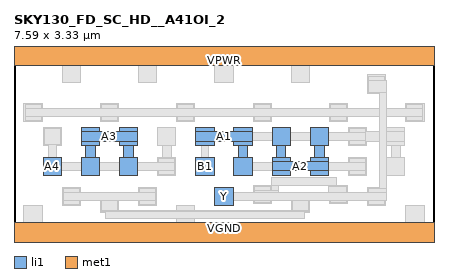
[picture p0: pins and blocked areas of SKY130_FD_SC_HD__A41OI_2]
MACRO SKY130_FD_SC_HD__A41OI_2
 CLASS CORE ;
 FOREIGN SKY130_FD_SC_HD__A41OI_2 0 0 ;
 SIZE 7.59 BY 3.33 ;
 ORIGIN 0 0 ;
 SYMMETRY X Y R90 ;
 SITE unit ;
  PIN VPWR
   DIRECTION INOUT ;
   USE POWER ;
   SHAPE ABUTMENT ;
    PORT
     CLASS CORE ;
       LAYER li1 ;
        RECT 0.00000000 3.09000000 7.59000000 3.57000000 ;
       LAYER met1 ;
        RECT 0.00000000 3.09000000 7.59000000 3.57000000 ;
    END
  END VPWR

  PIN VGND
   DIRECTION INOUT ;
   USE POWER ;
   SHAPE ABUTMENT ;
    PORT
     CLASS CORE ;
       LAYER li1 ;
        RECT 0.00000000 -0.24000000 7.59000000 0.24000000 ;
       LAYER met1 ;
        RECT 0.00000000 -0.24000000 7.59000000 0.24000000 ;
    END
  END VGND

  PIN Y
   DIRECTION INOUT ;
   USE SIGNAL ;
   SHAPE ABUTMENT ;
    PORT
     CLASS CORE ;
       LAYER li1 ;
        RECT 3.63000000 0.55500000 3.96000000 0.88500000 ;
    END
  END Y

  PIN A2
   DIRECTION INOUT ;
   USE SIGNAL ;
   SHAPE ABUTMENT ;
    PORT
     CLASS CORE ;
       LAYER li1 ;
        RECT 4.66500000 1.09500000 4.99500000 1.17500000 ;
        RECT 5.35500000 1.09500000 5.68500000 1.17500000 ;
        RECT 4.66500000 1.17500000 5.68500000 1.34500000 ;
        RECT 4.66500000 1.34500000 4.99500000 1.42500000 ;
        RECT 5.35500000 1.34500000 5.68500000 1.42500000 ;
        RECT 4.74500000 1.42500000 4.91500000 1.63500000 ;
        RECT 5.43500000 1.42500000 5.60500000 1.63500000 ;
        RECT 4.66500000 1.63500000 4.99500000 1.96500000 ;
        RECT 5.35500000 1.63500000 5.68500000 1.96500000 ;
    END
  END A2

  PIN A3
   DIRECTION INOUT ;
   USE SIGNAL ;
   SHAPE ABUTMENT ;
    PORT
     CLASS CORE ;
       LAYER li1 ;
        RECT 1.21500000 1.09500000 1.54500000 1.42500000 ;
        RECT 1.90500000 1.09500000 2.23500000 1.42500000 ;
        RECT 1.29500000 1.42500000 1.46500000 1.63500000 ;
        RECT 1.98500000 1.42500000 2.15500000 1.63500000 ;
        RECT 1.21500000 1.63500000 1.54500000 1.71500000 ;
        RECT 1.90500000 1.63500000 2.23500000 1.71500000 ;
        RECT 1.21500000 1.71500000 2.23500000 1.88500000 ;
        RECT 1.21500000 1.88500000 1.54500000 1.96500000 ;
        RECT 1.90500000 1.88500000 2.23500000 1.96500000 ;
    END
  END A3

  PIN A1
   DIRECTION INOUT ;
   USE SIGNAL ;
   SHAPE ABUTMENT ;
    PORT
     CLASS CORE ;
       LAYER li1 ;
        RECT 3.97500000 1.09500000 4.30500000 1.42500000 ;
        RECT 4.05500000 1.42500000 4.22500000 1.63500000 ;
        RECT 3.28500000 1.63500000 3.61500000 1.71500000 ;
        RECT 3.97500000 1.63500000 4.30500000 1.71500000 ;
        RECT 3.28500000 1.71500000 4.30500000 1.88500000 ;
        RECT 3.28500000 1.88500000 3.61500000 1.96500000 ;
        RECT 3.97500000 1.88500000 4.30500000 1.96500000 ;
    END
  END A1

  PIN A4
   DIRECTION INOUT ;
   USE SIGNAL ;
   SHAPE ABUTMENT ;
    PORT
     CLASS CORE ;
       LAYER li1 ;
        RECT 0.52500000 1.09500000 0.85500000 1.42500000 ;
    END
  END A4

  PIN B1
   DIRECTION INOUT ;
   USE SIGNAL ;
   SHAPE ABUTMENT ;
    PORT
     CLASS CORE ;
       LAYER li1 ;
        RECT 3.28500000 1.09500000 3.61500000 1.42500000 ;
    END
  END B1

 OBS
    LAYER polycont ;
     RECT 4.74500000 1.17500000 4.91500000 1.34500000 ;
     RECT 5.43500000 1.17500000 5.60500000 1.34500000 ;
     RECT 4.74500000 1.71500000 4.91500000 1.88500000 ;
     RECT 5.43500000 1.71500000 5.60500000 1.88500000 ;
     RECT 4.05500000 1.17500000 4.22500000 1.34500000 ;
     RECT 6.12500000 1.17500000 6.29500000 1.34500000 ;
     RECT 3.36500000 1.71500000 3.53500000 1.88500000 ;
     RECT 4.05500000 1.71500000 4.22500000 1.88500000 ;
     RECT 0.60500000 1.17500000 0.77500000 1.34500000 ;
     RECT 2.67500000 1.17500000 2.84500000 1.34500000 ;
     RECT 0.60500000 1.71500000 0.77500000 1.88500000 ;
     RECT 2.67500000 1.71500000 2.84500000 1.88500000 ;
     RECT 1.29500000 1.17500000 1.46500000 1.34500000 ;
     RECT 1.98500000 1.17500000 2.15500000 1.34500000 ;
     RECT 1.29500000 1.71500000 1.46500000 1.88500000 ;
     RECT 1.98500000 1.71500000 2.15500000 1.88500000 ;
     RECT 3.36500000 1.17500000 3.53500000 1.34500000 ;
     RECT 6.81500000 1.17500000 6.98500000 1.34500000 ;
     RECT 6.12500000 1.71500000 6.29500000 1.88500000 ;
     RECT 6.81500000 1.71500000 6.98500000 1.88500000 ;

    LAYER pdiffc ;
     RECT 6.47000000 2.66000000 6.64000000 2.83000000 ;
     RECT 0.95000000 2.86000000 1.12000000 3.03000000 ;
     RECT 2.33000000 2.86000000 2.50000000 3.03000000 ;
     RECT 3.71000000 2.86000000 3.88000000 3.03000000 ;
     RECT 5.09000000 2.86000000 5.26000000 3.03000000 ;
     RECT 0.26000000 2.15000000 0.43000000 2.32000000 ;
     RECT 1.64000000 2.15000000 1.81000000 2.32000000 ;
     RECT 3.02000000 2.15000000 3.19000000 2.32000000 ;
     RECT 4.40000000 2.15000000 4.57000000 2.32000000 ;
     RECT 5.78000000 2.15000000 5.95000000 2.32000000 ;
     RECT 7.16000000 2.15000000 7.33000000 2.32000000 ;

    LAYER ndiffc ;
     RECT 3.71000000 0.63500000 3.88000000 0.80500000 ;
     RECT 6.47000000 0.63500000 6.64000000 0.80500000 ;
     RECT 4.40000000 0.66000000 4.57000000 0.83000000 ;
     RECT 5.78000000 0.66000000 5.95000000 0.83000000 ;
     RECT 0.26000000 0.30000000 0.43000000 0.47000000 ;
     RECT 3.02000000 0.30000000 3.19000000 0.47000000 ;
     RECT 7.16000000 0.30000000 7.33000000 0.47000000 ;
     RECT 0.95000000 0.63500000 1.12000000 0.80500000 ;
     RECT 2.33000000 0.63500000 2.50000000 0.80500000 ;
     RECT 1.64000000 0.50000000 1.81000000 0.67000000 ;
     RECT 5.09000000 0.50000000 5.26000000 0.67000000 ;

    LAYER li1 ;
     RECT 3.63000000 0.55500000 3.96000000 0.88500000 ;
     RECT 6.39000000 0.55500000 6.72000000 0.88500000 ;
     RECT 6.39000000 2.58000000 6.72000000 2.91000000 ;
     RECT 4.66500000 1.09500000 4.99500000 1.17500000 ;
     RECT 5.35500000 1.09500000 5.68500000 1.17500000 ;
     RECT 4.66500000 1.17500000 5.68500000 1.34500000 ;
     RECT 4.66500000 1.34500000 4.99500000 1.42500000 ;
     RECT 5.35500000 1.34500000 5.68500000 1.42500000 ;
     RECT 4.74500000 1.42500000 4.91500000 1.63500000 ;
     RECT 5.43500000 1.42500000 5.60500000 1.63500000 ;
     RECT 4.66500000 1.63500000 4.99500000 1.96500000 ;
     RECT 5.35500000 1.63500000 5.68500000 1.96500000 ;
     RECT 0.87000000 2.78000000 1.20000000 3.09000000 ;
     RECT 2.25000000 2.78000000 2.58000000 3.09000000 ;
     RECT 3.63000000 2.78000000 3.96000000 3.09000000 ;
     RECT 5.01000000 2.78000000 5.34000000 3.09000000 ;
     RECT 0.00000000 3.09000000 7.59000000 3.57000000 ;
     RECT 6.04500000 1.09500000 6.37500000 1.42500000 ;
     RECT 3.97500000 1.09500000 4.30500000 1.42500000 ;
     RECT 4.05500000 1.42500000 4.22500000 1.63500000 ;
     RECT 3.28500000 1.63500000 3.61500000 1.71500000 ;
     RECT 3.97500000 1.63500000 4.30500000 1.71500000 ;
     RECT 3.28500000 1.71500000 4.30500000 1.88500000 ;
     RECT 3.28500000 1.88500000 3.61500000 1.96500000 ;
     RECT 3.97500000 1.88500000 4.30500000 1.96500000 ;
     RECT 4.32000000 0.58000000 4.65000000 0.91000000 ;
     RECT 5.70000000 0.58000000 6.03000000 0.91000000 ;
     RECT 0.18000000 2.07000000 0.51000000 2.40000000 ;
     RECT 1.56000000 2.07000000 1.89000000 2.40000000 ;
     RECT 2.94000000 2.07000000 3.27000000 2.40000000 ;
     RECT 4.32000000 2.07000000 4.65000000 2.40000000 ;
     RECT 5.70000000 2.07000000 6.03000000 2.40000000 ;
     RECT 7.08000000 2.07000000 7.41000000 2.40000000 ;
     RECT 0.00000000 -0.24000000 7.59000000 0.24000000 ;
     RECT 0.18000000 0.24000000 0.51000000 0.55000000 ;
     RECT 2.94000000 0.24000000 3.27000000 0.55000000 ;
     RECT 7.08000000 0.24000000 7.41000000 0.55000000 ;
     RECT 0.52500000 1.09500000 0.85500000 1.42500000 ;
     RECT 0.52500000 1.63500000 0.85500000 1.96500000 ;
     RECT 2.59500000 1.09500000 2.92500000 1.42500000 ;
     RECT 2.67500000 1.42500000 2.84500000 1.63500000 ;
     RECT 2.59500000 1.63500000 2.92500000 1.96500000 ;
     RECT 1.21500000 1.09500000 1.54500000 1.42500000 ;
     RECT 1.90500000 1.09500000 2.23500000 1.42500000 ;
     RECT 1.29500000 1.42500000 1.46500000 1.63500000 ;
     RECT 1.98500000 1.42500000 2.15500000 1.63500000 ;
     RECT 1.21500000 1.63500000 1.54500000 1.71500000 ;
     RECT 1.90500000 1.63500000 2.23500000 1.71500000 ;
     RECT 1.21500000 1.71500000 2.23500000 1.88500000 ;
     RECT 1.21500000 1.88500000 1.54500000 1.96500000 ;
     RECT 1.90500000 1.88500000 2.23500000 1.96500000 ;
     RECT 3.28500000 1.09500000 3.61500000 1.42500000 ;
     RECT 6.73500000 1.09500000 7.06500000 1.42500000 ;
     RECT 6.81500000 1.42500000 6.98500000 1.63500000 ;
     RECT 6.04500000 1.63500000 6.37500000 1.71500000 ;
     RECT 6.73500000 1.63500000 7.06500000 1.71500000 ;
     RECT 6.04500000 1.71500000 7.06500000 1.88500000 ;
     RECT 6.04500000 1.88500000 6.37500000 1.96500000 ;
     RECT 6.73500000 1.88500000 7.06500000 1.96500000 ;
     RECT 0.87000000 0.55500000 1.20000000 0.88500000 ;
     RECT 2.25000000 0.55500000 2.58000000 0.88500000 ;
     RECT 1.56000000 0.42000000 1.89000000 0.75000000 ;
     RECT 5.01000000 0.42000000 5.34000000 0.75000000 ;

    LAYER viali ;
     RECT 3.71000000 0.63500000 3.88000000 0.80500000 ;
     RECT 6.47000000 0.63500000 6.64000000 0.80500000 ;
     RECT 6.47000000 2.66000000 6.64000000 2.83000000 ;
     RECT 2.33000000 3.24500000 2.50000000 3.41500000 ;
     RECT 4.05500000 1.17500000 4.22500000 1.34500000 ;
     RECT 6.12500000 1.17500000 6.29500000 1.34500000 ;
     RECT 4.40000000 0.66000000 4.57000000 0.83000000 ;
     RECT 5.78000000 0.66000000 5.95000000 0.83000000 ;
     RECT 0.26000000 2.15000000 0.43000000 2.32000000 ;
     RECT 1.64000000 2.15000000 1.81000000 2.32000000 ;
     RECT 3.02000000 2.15000000 3.19000000 2.32000000 ;
     RECT 4.40000000 2.15000000 4.57000000 2.32000000 ;
     RECT 5.78000000 2.15000000 5.95000000 2.32000000 ;
     RECT 7.16000000 2.15000000 7.33000000 2.32000000 ;
     RECT 3.02000000 -0.08500000 3.19000000 0.08500000 ;
     RECT 0.60500000 1.17500000 0.77500000 1.34500000 ;
     RECT 2.67500000 1.17500000 2.84500000 1.34500000 ;
     RECT 0.60500000 1.71500000 0.77500000 1.88500000 ;
     RECT 3.36500000 1.17500000 3.53500000 1.34500000 ;
     RECT 6.12500000 1.71500000 6.29500000 1.88500000 ;
     RECT 0.95000000 0.63500000 1.12000000 0.80500000 ;
     RECT 2.33000000 0.63500000 2.50000000 0.80500000 ;
     RECT 1.64000000 0.50000000 1.81000000 0.67000000 ;
     RECT 5.09000000 0.50000000 5.26000000 0.67000000 ;

    LAYER met1 ;
     RECT 4.63000000 0.81500000 4.64500000 0.89000000 ;
     RECT 3.65000000 0.57500000 3.94000000 0.86500000 ;
     RECT 6.41000000 0.57500000 6.70000000 0.86500000 ;
     RECT 6.41000000 2.60000000 6.70000000 2.89000000 ;
     RECT 0.00000000 3.09000000 7.59000000 3.57000000 ;
     RECT 3.99500000 1.11500000 4.28500000 1.40500000 ;
     RECT 6.06500000 1.11500000 6.35500000 1.40500000 ;
     RECT 4.34000000 0.60000000 4.63000000 0.67500000 ;
     RECT 5.72000000 0.60000000 6.01000000 0.67500000 ;
     RECT 4.34000000 0.67500000 4.78500000 0.81500000 ;
     RECT 4.34000000 0.81500000 4.63000000 0.89000000 ;
     RECT 5.68000000 0.67500000 6.01000000 0.89000000 ;
     RECT 4.64500000 0.81500000 4.78500000 0.92000000 ;
     RECT 5.68000000 0.89000000 5.82000000 0.92000000 ;
     RECT 4.64500000 0.92000000 5.82000000 1.06000000 ;
     RECT 0.20000000 2.09000000 0.49000000 2.16500000 ;
     RECT 1.58000000 2.09000000 1.87000000 2.16500000 ;
     RECT 2.96000000 2.09000000 3.25000000 2.16500000 ;
     RECT 4.34000000 2.09000000 4.63000000 2.16500000 ;
     RECT 5.72000000 2.09000000 6.01000000 2.16500000 ;
     RECT 7.10000000 2.09000000 7.39000000 2.16500000 ;
     RECT 0.20000000 2.16500000 7.39000000 2.30500000 ;
     RECT 0.20000000 2.30500000 0.49000000 2.38000000 ;
     RECT 1.58000000 2.30500000 1.87000000 2.38000000 ;
     RECT 2.96000000 2.30500000 3.25000000 2.38000000 ;
     RECT 4.34000000 2.30500000 4.63000000 2.38000000 ;
     RECT 5.72000000 2.30500000 6.01000000 2.38000000 ;
     RECT 7.10000000 2.30500000 7.39000000 2.38000000 ;
     RECT 0.00000000 -0.24000000 7.59000000 0.24000000 ;
     RECT 0.54500000 1.11500000 0.83500000 1.19000000 ;
     RECT 2.61500000 1.11500000 2.90500000 1.19000000 ;
     RECT 0.54500000 1.19000000 2.90500000 1.33000000 ;
     RECT 0.54500000 1.33000000 0.83500000 1.40500000 ;
     RECT 2.61500000 1.33000000 2.90500000 1.40500000 ;
     RECT 0.62000000 1.40500000 0.76000000 1.65500000 ;
     RECT 0.54500000 1.65500000 0.83500000 1.94500000 ;
     RECT 3.30500000 1.11500000 3.59500000 1.40500000 ;
     RECT 3.38000000 1.40500000 3.52000000 1.73000000 ;
     RECT 6.06500000 1.65500000 6.35500000 1.73000000 ;
     RECT 3.38000000 1.73000000 6.35500000 1.87000000 ;
     RECT 6.06500000 1.87000000 6.35500000 1.94500000 ;
     RECT 0.89000000 0.57500000 1.18000000 0.86500000 ;
     RECT 2.27000000 0.57500000 2.56000000 0.86500000 ;
     RECT 1.65500000 0.31500000 5.24500000 0.44000000 ;
     RECT 1.58000000 0.44000000 5.32000000 0.45500000 ;
     RECT 1.58000000 0.45500000 1.87000000 0.73000000 ;
     RECT 5.03000000 0.45500000 5.32000000 0.73000000 ;

    LAYER via ;
     RECT 3.71000000 0.63500000 3.88000000 0.80500000 ;
     RECT 6.47000000 0.63500000 6.64000000 0.80500000 ;
     RECT 6.47000000 2.66000000 6.64000000 2.83000000 ;
     RECT 4.05500000 1.17500000 4.22500000 1.34500000 ;
     RECT 6.12500000 1.17500000 6.29500000 1.34500000 ;
     RECT 0.95000000 0.63500000 1.12000000 0.80500000 ;
     RECT 2.33000000 0.63500000 2.50000000 0.80500000 ;

    LAYER met2 ;
     RECT 3.65000000 0.57500000 3.94000000 0.65000000 ;
     RECT 6.41000000 0.57500000 6.70000000 0.65000000 ;
     RECT 3.65000000 0.65000000 6.74000000 0.79000000 ;
     RECT 3.65000000 0.79000000 3.94000000 0.86500000 ;
     RECT 6.41000000 0.79000000 6.74000000 0.86500000 ;
     RECT 6.60000000 0.86500000 6.74000000 2.60000000 ;
     RECT 6.41000000 2.60000000 6.74000000 2.81500000 ;
     RECT 6.41000000 2.81500000 6.70000000 2.89000000 ;
     RECT 3.99500000 1.11500000 4.28500000 1.19000000 ;
     RECT 6.06500000 1.11500000 6.35500000 1.19000000 ;
     RECT 3.99500000 1.19000000 6.35500000 1.33000000 ;
     RECT 3.99500000 1.33000000 4.28500000 1.40500000 ;
     RECT 6.06500000 1.33000000 6.35500000 1.40500000 ;
     RECT 0.89000000 0.57500000 1.18000000 0.65000000 ;
     RECT 2.27000000 0.57500000 2.56000000 0.65000000 ;
     RECT 0.89000000 0.65000000 2.56000000 0.79000000 ;
     RECT 0.89000000 0.79000000 1.18000000 0.86500000 ;
     RECT 2.27000000 0.79000000 2.56000000 0.86500000 ;

    LAYER via2 ;


    LAYER met3 ;


 END
END SKY130_FD_SC_HD__A41OI_2
